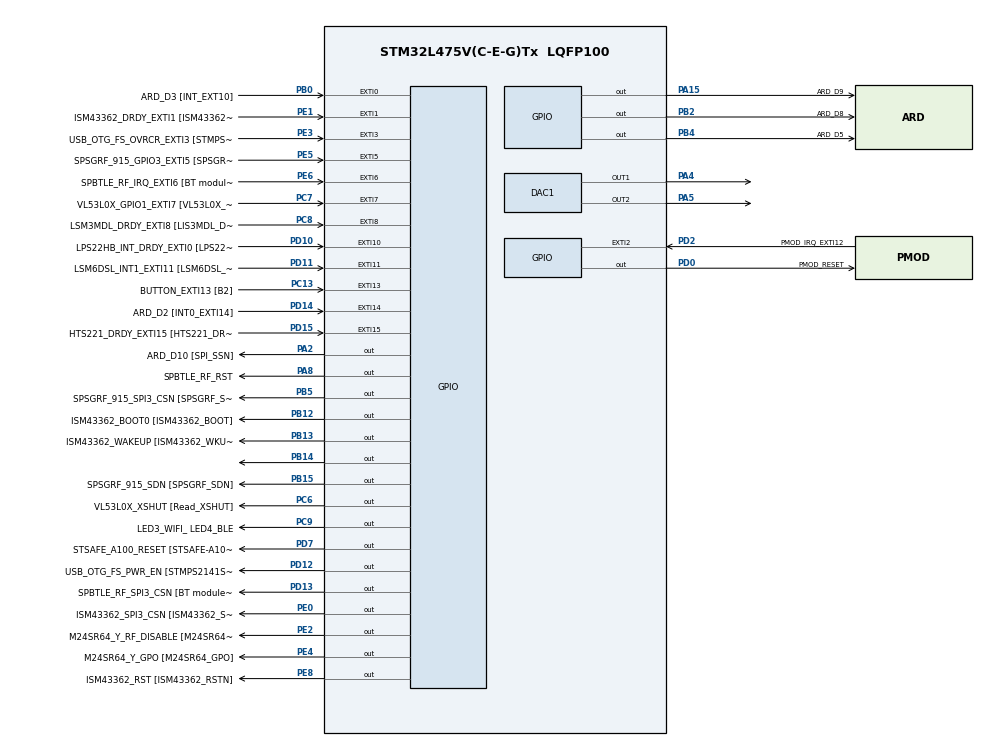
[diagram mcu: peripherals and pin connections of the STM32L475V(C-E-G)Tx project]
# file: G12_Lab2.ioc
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DAC1.DAC_Channel-DAC_OUT2=DAC_CHANNEL_2
Mcu.Family=STM32L4
Mcu.Name=STM32L475V(C-E-G)Tx
Mcu.Package=LQFP100
NVIC.EXTI15_10_IRQn=true\:0\:0\:false\:false\:true\:true
NVIC.EXTI9_5_IRQn=true\:0\:0\:false\:false\:true\:true
NVIC.PriorityGroup=NVIC_PRIORITYGROUP_4
PA0.GPIO_Label=ARD_D1 [UART4_TX]
PA0.Signal=UART4_TX
PA1.GPIO_Label=ARD_D0 [UART4_RX]
PA1.Signal=UART4_RX
PA10.GPIO_Label=USB_OTG_FS_ID
PA10.Signal=USB_OTG_FS_ID
PA11.GPIO_Label=USB_OTG_FS_DM
PA11.Signal=USB_OTG_FS_DM
PA12.GPIO_Label=USB_OTG_FS_DP
PA12.Signal=USB_OTG_FS_DP
PA13\ (JTMS-SWDIO).GPIO_Label=SYS_JTMS_SWDIO
PA13\ (JTMS-SWDIO).Signal=SYS_JTMS-SWDIO
PA14\ (JTCK-SWCLK).GPIO_Label=SYS_JTCK_SWCLK
PA14\ (JTCK-SWCLK).Signal=SYS_JTCK-SWCLK
PA15\ (JTDI).GPIO_Label=ARD_D9
PA15\ (JTDI).Signal=GPIO_Output
PA2.GPIO_Label=ARD_D10 [SPI_SSN]
PA2.Signal=GPIO_Output
PA3.GPIO_Label=ARD_D4
PA3.Signal=S_TIM2_CH4
PA4.Signal=COMP_DAC11_group
PA5.Signal=COMP_DAC12_group
PA6.GPIO_Label=ARD_D12 [SPI1_MISO]
PA6.Signal=SPI1_MISO
PA7.GPIO_Label=ARD_D11 [SPI1_MOSI]
PA7.Signal=SPI1_MOSI
PA8.GPIO_Label=SPBTLE_RF_RST
PA8.Signal=GPIO_Output
PA9.GPIO_Label=USB_OTG_FS_VBUS [STMPS2141STR_OUT]
PA9.Signal=USB_OTG_FS_VBUS
PB0.GPIO_Label=ARD_D3 [INT_EXT10]
PB0.Signal=GPXTI0
PB1.GPIO_Label=ARD_D6 [ADC1_IN6]
PB1.Signal=ADCx_IN16
PB10.GPIO_Label=INTERNAL_I2C2_SCL [VL53L0X_SCL]
PB10.Signal=I2C2_SCL
PB11.GPIO_Label=INTERNAL_I2C2_SDA [VL53L0X_SDA]
PB11.Signal=I2C2_SDA
PB12.GPIO_Label=ISM43362_BOOT0 [ISM43362_BOOT]
PB12.Signal=GPIO_Output
PB13.GPIO_Label=ISM43362_WAKEUP [ISM43362_WKUP]
PB13.Signal=GPIO_Output
PB14.Signal=GPIO_Output
PB15.GPIO_Label=SPSGRF_915_SDN [SPSGRF_SDN]
PB15.Signal=GPIO_Output
PB2.GPIO_Label=ARD_D8
PB2.Signal=GPIO_Output
PB3\ (JTDO-TRACESWO).GPIO_Label=SYS_JTD0_SWO
PB3\ (JTDO-TRACESWO).Signal=SYS_JTDO-SWO
PB4\ (NJTRST).GPIO_Label=ARD_D5
PB4\ (NJTRST).Signal=GPIO_Output
PB5.GPIO_Label=SPSGRF_915_SPI3_CSN [SPSGRF_SPI_CS]
PB5.Signal=GPIO_Output
PB6.GPIO_Label=ST_LINK_UART1_TX
PB6.Signal=USART1_TX
PB7.GPIO_Label=ST_LINK_UART1_RX
PB7.Signal=USART1_RX
PB8.GPIO_Label=ARD_D15 [I2C1_SCL]
PB8.Signal=I2C1_SCL
PB9.GPIO_Label=ARD_D14 [I2C1_SDA]
PB9.Signal=I2C1_SDA
PC0.GPIO_Label=ARD_A5 [ADC]
PC0.Signal=ADCx_IN1
PC1.GPIO_Label=ARD_A4 [ADC]
PC1.Signal=ADCx_IN2
PC10.GPIO_Label=INTERNAL_SPI3_SCK [BT module_SPI_SCLK]
PC10.Signal=SPI3_SCK
PC11.GPIO_Label=INTERNAL_SPI3_MISO [BT module_SPI_MISO]
PC11.Signal=SPI3_MISO
PC12.GPIO_Label=INTERNAL_SPI3_MOSI [BT module_SPI_MOSI]
PC12.Signal=SPI3_MOSI
PC13.GPIO_Label=BUTTON_EXTI13 [B2]
PC13.GPIO_ModeDefaultEXTI=GPIO_MODE_IT_FALLING
PC13.Signal=GPXTI13
PC14-OSC32_IN\ (PC14).Signal=RCC_OSC32_IN
PC15-OSC32_OUT\ (PC15).Signal=RCC_OSC32_OUT
PC2.GPIO_Label=ARD_A3 [ADC]
PC2.Signal=ADCx_IN3
PC3.GPIO_Label=ARD_A2 [ADC]
PC3.Signal=ADCx_IN4
PC4.GPIO_Label=ARD_A1 [ADC]
PC4.Signal=ADCx_IN13
PC5.GPIO_Label=ARD_A0 [ADC]
PC5.Signal=ADCx_IN14
PC6.GPIO_Label=VL53L0X_XSHUT [Read_XSHUT]
PC6.Signal=GPIO_Output
PC7.GPIO_Label=VL53L0X_GPIO1_EXTI7 [VL53L0X_GPIO1]
PC7.Signal=GPXTI7
PC8.GPIO_Label=LSM3MDL_DRDY_EXTI8 [LIS3MDL_DRDY]
PC8.Signal=GPXTI8
PC9.GPIO_Label=LED3_WIFI_ LED4_BLE
PC9.Signal=GPIO_Output
PD0.GPIO_Label=PMOD_RESET
PD0.Signal=GPIO_Output
PD1.GPIO_Label=PMOD_SPI2_SCK
PD1.Signal=SPI2_SCK
PD10.GPIO_Label=LPS22HB_INT_DRDY_EXTI0 [LPS22HB_INT_DRDY] 
PD10.Signal=GPXTI10
PD11.GPIO_Label=LSM6DSL_INT1_EXTI11 [LSM6DSL_INT1]
PD11.Signal=GPXTI11
PD12.GPIO_Label=USB_OTG_FS_PWR_EN [STMPS2141STR_EN]
PD12.Signal=GPIO_Output
PD13.GPIO_Label=SPBTLE_RF_SPI3_CSN [BT module_SPI_CS]
PD13.Signal=GPIO_Output
PD14.GPIO_Label=ARD_D2 [INT0_EXTI14]
PD14.Signal=GPXTI14
PD15.GPIO_Label=HTS221_DRDY_EXTI15 [HTS221_DRDY]
PD15.Signal=GPXTI15
PD2.GPIO_Label=PMOD_IRQ_EXTI12
PD2.Signal=GPXTI2
PD3.GPIO_Label=PMOD_UART2_CTS
PD3.Signal=USART2_CTS
PD4.GPIO_Label=PMOD_UART2_RTS
PD4.Signal=USART2_RTS
PD5.GPIO_Label=PMOD_UART2_TX
PD5.Signal=USART2_TX
PD6.GPIO_Label=PMOD_UART2_RX
PD6.Signal=USART2_RX
PD7.GPIO_Label=STSAFE_A100_RESET [STSAFE-A100_RESET]
PD7.Signal=GPIO_Output
PD8.GPIO_Label=INTERNAL_UART3_TX [ISM43362_RX]
PD8.Signal=USART3_TX
PD9.GPIO_Label=INTERNAL_UART3_RX [ISM43362_TX]
PD9.Signal=USART3_RX
PE0.GPIO_Label=ISM43362_SPI3_CSN [ISM43362_SSN]
PE0.Signal=GPIO_Output
PE1.GPIO_Label=ISM43362_DRDY_EXTI1 [ISM43362_DATARDY]
PE1.Signal=GPXTI1
PE10.GPIO_Label=QUADSPI_CLK [MX25R6435F_SCLK]
PE10.Signal=QUADSPI_CLK
PE11.GPIO_Label=QUADSPI_NCS [MX25R6435F_SCLK]
PE11.Signal=QUADSPI_NCS
PE12.GPIO_Label=OQUADSPI_BK1_IO0 [MX25R6435F_IO0]
PE12.Signal=QUADSPI_BK1_IO0
PE13.GPIO_Label=QUADSPI_BK1_IO1 [MX25R6435F_IO1]
PE13.Signal=QUADSPI_BK1_IO1
PE14.GPIO_Label=QUAD_SPI_BK1_IO2 [MX25R6435F_IO2]
PE14.Signal=QUADSPI_BK1_IO2
PE15.GPIO_Label=QUAD_SPI_BK1_IO3 [MX25R6435F_IO3]
PE15.Signal=QUADSPI_BK1_IO3
PE2.GPIO_Label=M24SR64_Y_RF_DISABLE [M24SR64_RFDIS]
PE2.Signal=GPIO_Output
PE3.GPIO_Label=USB_OTG_FS_OVRCR_EXTI3 [STMPS2141STR_FAULT]
PE3.Signal=GPXTI3
PE4.GPIO_Label=M24SR64_Y_GPO [M24SR64_GPO]
PE4.Signal=GPIO_Output
PE5.GPIO_Label=SPSGRF_915_GPIO3_EXTI5 [SPSGRF_GPIO_3]
PE5.Signal=GPXTI5
PE6.GPIO_Label=SPBTLE_RF_IRQ_EXTI6 [BT module_SPI_IRQ]
PE6.Signal=GPXTI6
PE7.GPIO_Label=DFSDM1_DATIN2 [MP34DT01_DOUT]
PE7.Signal=S_DATAIN2DFSDM1
PE8.GPIO_Label=ISM43362_RST [ISM43362_RSTN]
PE8.Signal=GPIO_Output
PE9.GPIO_Label=DFSDM1_CKOUT [MP34DT01_CLK]
PE9.Signal=S_CKOUTDFSDM1
PH0-OSC_IN\ (PH0).Mode=HSE-External-Oscillator
PH0-OSC_IN\ (PH0).Signal=RCC_OSC_IN
PH1-OSC_OUT\ (PH1).Mode=HSE-External-Oscillator
PH1-OSC_OUT\ (PH1).Signal=RCC_OSC_OUT
RCC.ADCFreq_Value=48000000
RCC.AHBFreq_Value=80000000
RCC.APB1Freq_Value=80000000
RCC.APB1TimFreq_Value=80000000
RCC.APB2Freq_Value=80000000
RCC.APB2TimFreq_Value=80000000
RCC.CortexFreq_Value=80000000
RCC.HCLKFreq_Value=80000000
RCC.HSE_VALUE=8000000
RCC.HSI_VALUE=16000000
RCC.LSE_VALUE=32768
RCC.MSI_VALUE=4000000
RCC.PLLN=40
RCC.PLLSAI1N=24
RCC.SYSCLKFreq_VALUE=80000000
RCC.SYSCLKSource=RCC_SYSCLKSOURCE_PLLCLK
RCC.USBFreq_Value=48000000
RCC.VCOOutputFreq_Value=160000000
SH.ADCx_IN1.0=ADC1_IN1
SH.ADCx_IN13.0=ADC1_IN13
SH.ADCx_IN14.0=ADC1_IN14
SH.ADCx_IN16.0=ADC1_IN16
SH.ADCx_IN2.0=ADC1_IN2
SH.ADCx_IN3.0=ADC1_IN3
SH.ADCx_IN4.0=ADC1_IN4
SH.COMP_DAC11_group.0=DAC1_OUT1,DAC_OUT1
SH.COMP_DAC12_group.0=DAC1_OUT2,DAC_OUT2
SH.S_CKOUTDFSDM1.0=DFSDM1_CKOUT
SH.S_DATAIN2DFSDM1.0=DFSDM1_DATIN2
SH.S_TIM2_CH4.0=TIM2_CH4
board=B-L475E-IOT01A

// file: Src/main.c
#include "main.h"
#include "stm32l4xx_hal.h"

DAC_HandleTypeDef hdac1;

void SystemClock_Config(void);
static void MX_GPIO_Init(void);
static void MX_DAC1_Init(void);

int main(void)
{
  /* Reset of all peripherals, Initializes the Flash interface and the Systick. */
  HAL_Init();

  /* Configure the system clock */
  SystemClock_Config();

  /* Initialize all configured peripherals (GPIO and DAC) */
  MX_GPIO_Init();
  MX_DAC1_Init();

	/* Turn on LED */
	// HAL_GPIO_WritePin(GPIOB, GPIO_PIN_14, GPIO_PIN_SET);  // unnecessary

  /* Infinite loop */
	HAL_DAC_Start(&hdac1, DAC_CHANNEL_1);

			// triangle
		HAL_DAC_Start(&hdac1, DAC_CHANNEL_2);
		HAL_DACEx_TriangleWaveGenerate(&hdac1, DAC_CHANNEL_2, 4096);	// generate triangle

	int counter = 0;
  while (1)
  {
		//********** Student code here *************//
		if (HAL_GPIO_ReadPin(GPIOC, GPIO_PIN_13) != GPIO_PIN_SET) {				// if the button is pressed, turn on the light
      HAL_GPIO_WritePin(GPIOB, GPIO_PIN_14, GPIO_PIN_SET);
    } else {
			HAL_GPIO_WritePin(GPIOB, GPIO_PIN_14, GPIO_PIN_RESET);
		}

		// sawtooth
		HAL_DAC_SetValue(&hdac1, DAC_CHANNEL_1, DAC_ALIGN_8B_R, counter);	// send value to DAC
		counter++;
		if (counter >= 255) {																							// increment DAC value until we reach the max, then reset
			counter = 0;
		}
  }
}

void SystemClock_Config(void)
{

  RCC_OscInitTypeDef RCC_OscInitStruct;
  RCC_ClkInitTypeDef RCC_ClkInitStruct;

    /**Initializes the CPU, AHB and APB busses clocks
    */
  RCC_OscInitStruct.OscillatorType = RCC_OSCILLATORTYPE_MSI;
  RCC_OscInitStruct.MSIState = RCC_MSI_ON;
  RCC_OscInitStruct.MSICalibrationValue = 0;
  RCC_OscInitStruct.MSIClockRange = RCC_MSIRANGE_6;
  RCC_OscInitStruct.PLL.PLLState = RCC_PLL_NONE;
  if (HAL_RCC_OscConfig(&RCC_OscInitStruct) != HAL_OK)
  {
    _Error_Handler(__FILE__, __LINE__);
  }

    /**Initializes the CPU, AHB and APB busses clocks
    */
  RCC_ClkInitStruct.ClockType = RCC_CLOCKTYPE_HCLK|RCC_CLOCKTYPE_SYSCLK
                              |RCC_CLOCKTYPE_PCLK1|RCC_CLOCKTYPE_PCLK2;
  RCC_ClkInitStruct.SYSCLKSource = RCC_SYSCLKSOURCE_MSI;
  RCC_ClkInitStruct.AHBCLKDivider = RCC_SYSCLK_DIV1;
  RCC_ClkInitStruct.APB1CLKDivider = RCC_HCLK_DIV1;
  RCC_ClkInitStruct.APB2CLKDivider = RCC_HCLK_DIV1;

  if (HAL_RCC_ClockConfig(&RCC_ClkInitStruct, FLASH_LATENCY_0) != HAL_OK)
  {
    _Error_Handler(__FILE__, __LINE__);
  }

    /**Configure the main internal regulator output voltage
    */
  if (HAL_PWREx_ControlVoltageScaling(PWR_REGULATOR_VOLTAGE_SCALE1) != HAL_OK)
  {
    _Error_Handler(__FILE__, __LINE__);
  }

    /**Configure the Systick interrupt time
    */
  HAL_SYSTICK_Config(HAL_RCC_GetHCLKFreq()/1000);

    /**Configure the Systick
    */
  HAL_SYSTICK_CLKSourceConfig(SYSTICK_CLKSOURCE_HCLK);

  /* SysTick_IRQn interrupt configuration */
  HAL_NVIC_SetPriority(SysTick_IRQn, 0, 0);
}

/* DAC1 init function */
static void MX_DAC1_Init(void)
{
  DAC_ChannelConfTypeDef sConfig;

  /**DAC Initialization */
  hdac1.Instance = DAC1;
  if (HAL_DAC_Init(&hdac1) != HAL_OK)
  {
    _Error_Handler(__FILE__, __LINE__);
  }

  /**DAC channel OUT1 config*/
  sConfig.DAC_SampleAndHold = DAC_SAMPLEANDHOLD_DISABLE;
  sConfig.DAC_Trigger = DAC_TRIGGER_NONE;
  sConfig.DAC_OutputBuffer = DAC_OUTPUTBUFFER_ENABLE;
  sConfig.DAC_ConnectOnChipPeripheral = DAC_CHIPCONNECT_DISABLE;
  sConfig.DAC_UserTrimming = DAC_TRIMMING_FACTORY;
  if (HAL_DAC_ConfigChannel(&hdac1, &sConfig, DAC_CHANNEL_1) != HAL_OK)
  {
    _Error_Handler(__FILE__, __LINE__);
  }

  /**DAC channel OUT2 config */
  sConfig.DAC_ConnectOnChipPeripheral = DAC_CHIPCONNECT_DISABLE;
  if (HAL_DAC_ConfigChannel(&hdac1, &sConfig, DAC_CHANNEL_2) != HAL_OK)
  {
    _Error_Handler(__FILE__, __LINE__);
  }
}

/* GPIO init function */
static void MX_GPIO_Init(void)
{

  GPIO_InitTypeDef GPIO_InitStruct;

  /* GPIO Ports Clock Enable */
  __HAL_RCC_GPIOC_CLK_ENABLE();
  __HAL_RCC_GPIOA_CLK_ENABLE();
  __HAL_RCC_GPIOB_CLK_ENABLE();

  /*Configure GPIO pin Output Level */
  HAL_GPIO_WritePin(GPIOB, GPIO_PIN_14, GPIO_PIN_RESET);

  /*Configure GPIO pin : PC13 */
  GPIO_InitStruct.Pin = GPIO_PIN_13;
  GPIO_InitStruct.Mode = GPIO_MODE_INPUT;
  GPIO_InitStruct.Pull = GPIO_NOPULL;
  HAL_GPIO_Init(GPIOC, &GPIO_InitStruct);

  /*Configure GPIO pin : PB14 */
  GPIO_InitStruct.Pin = GPIO_PIN_14;
  GPIO_InitStruct.Mode = GPIO_MODE_OUTPUT_PP;
  GPIO_InitStruct.Pull = GPIO_NOPULL;
  GPIO_InitStruct.Speed = GPIO_SPEED_FREQ_LOW;
  HAL_GPIO_Init(GPIOB, &GPIO_InitStruct);
}

void _Error_Handler(char *file, int line)
{
  /* User can add his own implementation to report the HAL error return state */
  while(1)
  {
  }
}
